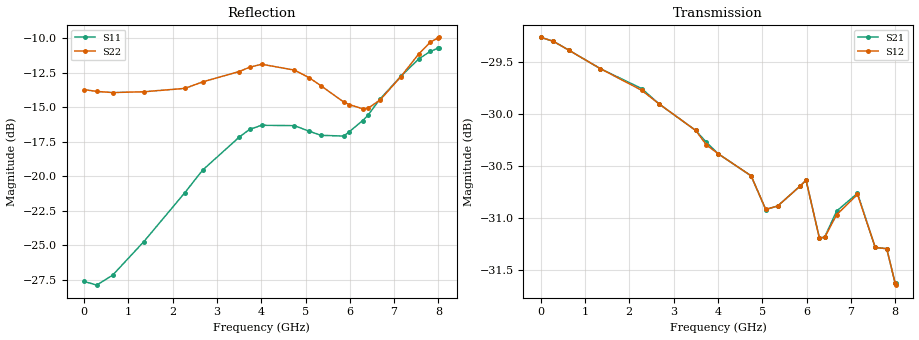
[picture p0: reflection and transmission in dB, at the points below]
! DEVICE ID: PE43712
! File Path: z:\PE43713\PE43713_CHAR_NOM_04292014\AMB\3p300\LS_ATT_28p00dB\PE43713_AMB_3p300V_3p000V_0p000V_LS_ATT_28p00dB_S2P_SN_10_A0139A.s2p
! Serial: 10
! Lot: A0139A
! Temp: 25C
! VDD: 3.300
! VSS: 0.000
! Control_Hi: 3.000
! Control_Lo: 0.000
! Attenuation Step: 28.00dB
! Port 1: RF1
! Port 2: RF2
! ThroughPath:1-2
! IDD: 0.0001455326
! ISS: -9.96e-008
#  Hz  S  RI  R  50
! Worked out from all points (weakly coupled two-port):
!   801 points, 10 MHz to 8.01 GHz, reference 50 ohm
!   highest |S21| = -29.26 dB at 10 MHz (marker M1); lowest = -31.6 dB at 8 GHz (marker M2)
!   lowest |S11| = -27.9 dB at 290 MHz (marker M3), VSWR 1.08, Z = 46.3 + j1.23 ohm
!   |S11| at or under -10 dB: start of sweep to end of sweep
!   |S22| runs from -15.1 to -9.9 dB; largest |S21 - S12| = 0.00013
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1e7  -0.0416 0.000883  0.0344 -0.000153  0.0344 -0.000117  -0.2059 0.00136
2.9e8  -0.0381 0.0133  0.0341 -0.00322  0.0341 -0.00321  -0.2016 0.0222
6.5e8  -0.0337 0.0281  0.0332 -0.00689  0.0332 -0.00689  -0.1952 0.0479
1.35e9  -0.021 0.054  0.0305 -0.0132  0.0305 -0.0132  -0.1782 0.0957
2.28e9  0.00951 0.0868  0.0254 -0.0203  0.0254 -0.0202  -0.1369 0.1567
2.68e9  0.025 0.1023  0.0226 -0.0226  0.0226 -0.0226  -0.1143 0.1876
3.5e9  0.0483 0.1297  0.0165 -0.0263  0.0165 -0.0263  -0.0788 0.226
3.74e9  0.0533 0.1379  0.0145 -0.027  0.0145 -0.0269  -0.0727 0.2373
4.01e9  0.0582 0.1415  0.0124 -0.0276  0.0124 -0.0276  -0.0673 0.2454
4.75e9  0.072 0.1344  0.00695 -0.0287  0.00697 -0.0287  -0.0399 0.239
5.08e9  0.0815 0.1207  0.00449 -0.0281  0.00452 -0.0281  -0.0267 0.226
5.35e9  0.091 0.1073  0.00308 -0.0284  0.00308 -0.0284  -0.0141 0.2121
5.86e9  0.1172 0.0762  -0.000709 -0.0292  -0.000654 -0.0292  0.032 0.183
5.99e9  0.1268 0.0704  -0.00234 -0.0293  -0.0023 -0.0293  0.0466 0.1756
6.29e9  0.1493 0.0552  -0.00393 -0.0273  -0.00388 -0.0273  0.0852 0.1535
6.41e9  0.1583 0.0514  -0.00411 -0.0273  -0.00403 -0.0273  0.1007 0.1447
6.68e9  0.1852 0.0435  -0.00585 -0.0278  -0.00577 -0.0277  0.1373 0.1295
7.15e9  0.2272 0.0361  -0.0105 -0.027  -0.0104 -0.027  0.1957 0.1197
7.55e9  0.2629 0.0373  -0.013 -0.024  -0.013 -0.024  0.2485 0.1215
7.81e9  0.2801 0.0407  -0.0143 -0.0232  -0.0143 -0.0232  0.2783 0.1253
8e9  0.2882 0.0428  -0.0146 -0.0218  -0.0146 -0.0218  0.2923 0.1243
8.01e9  0.2886 0.0434  -0.0146 -0.0218  -0.0145 -0.0218  0.2931 0.1241
